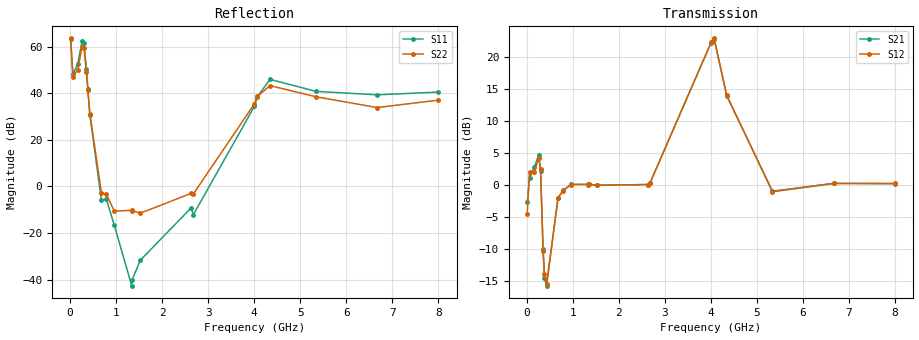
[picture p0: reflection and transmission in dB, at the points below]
!Agilent Technologies,N5230A,US43500312,A.07.50.67
!Agilent N5230A: A.07.50.67
!Date: Tuesday, June 09, 2015 15:38:11
!Correction: S11(Full 2 Port(1,2))
!S21(Full 2 Port(1,2))
!S12(Full 2 Port(1,2))
!S22(Full 2 Port(1,2))
!S2P File: Measurements: S11, S21, S12, S22:
# Hz S  MA  R 50
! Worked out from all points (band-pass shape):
!   1601 points, 10 MHz to 8 GHz, reference 50 ohm
!   highest |S21| = 22.90 dB at 4.07 GHz (marker M1); lowest = -15.7 dB at 429.5 MHz (marker M2)
!   |S21| within 3 dB of the highest: 3.919 GHz to 4.221 GHz (302.2 MHz wide, 7.43 % of centre)
!   lowest |S11| = -42.7 dB at 1.338 GHz (marker M3), VSWR 1.01, Z = 49.7 - j0.686 ohm
!   |S11| at or under -10 dB: 865.1 MHz to 2.134 GHz (1.269 GHz wide, 84.6 % of centre); 2.647 GHz to 2.845 GHz (197.8 MHz wide, 7.2 % of centre); 3.433 GHz to 3.482 GHz (48.8 MHz wide, 1.41 % of centre)
!   |S22| runs from -13.3 to 63.6 dB; largest |S21 - S12| = 0.38
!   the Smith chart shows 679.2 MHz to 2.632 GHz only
!   S11 on the Smith chart (normalised r, x): 679.2 MHz: 0.33, +0.14; 789 MHz: 0.35, -0.35; 958.8 MHz: 1.23, -0.24; 1.528 GHz: 0.95, +0.02; 2.632 GHz: 0.59, -0.40
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1e7  1494 171.1  0.7352 -1.6  0.5969 -32.9  1520 -19.4
5.99375e7  254.6 328.2  1.136 2.2  1.276 0.2  228.7 92.8
1.648062e8  426.6 407.6  1.376 10.1  1.261 9.7  321.2 128.4
2.596875e8  1316 407.2  1.732 8.4  1.636 3.4  1001 121.8
2.996375e8  1194 419.6  1.277 28.9  1.329 32.2  944.9 137.5
3.545688e8  327.8 460.0  0.3139 64.0  0.3047 64.3  287.3 187.5
3.845312e8  126.8 459.7  0.1863 51.8  0.2015 42.9  119.5 195.8
4.29475e8  34.12 460.3  0.1635 42.8  0.1677 41.7  36.76 213.5
6.791625e8  0.5164 522.1  0.7982 110.1  0.7933 110.4  0.7386 400.6
7.89025e8  0.5249 582.6  0.9071 85.3  0.9021 85.0  0.6739 487.4
9.588125e8  0.1483 679.7  1.012 79.3  1.009 79.3  0.2963 576.3
1.338338e9  0.007369 609.3  1.011 82.1  1.01 82.2  0.3068 756.6
1.343331e9  0.00971 581.3  1.011 82.1  1.012 82.2  0.303 759.1
1.5281e9  0.02613 520.3  0.9961 82.1  0.9981 82.1  0.2668 845.8
2.631719e9  0.3474 238.7  1.009 86.0  1.01 86.1  0.7112 1204.7
2.676662e9  0.2464 243.7  1.034 86.4  1.038 86.4  0.6886 1217.1
4.005e9  52.67 346.2  12.99 82.9  13.02 83.2  59.43 1528.6
4.069919e9  85.4 345.6  13.97 55.1  14.02 55.4  86.62 1518.7
4.344575e9  199.9 282.0  4.993 -44.4  5.022 -44.3  146.6 1450.8
5.338331e9  110.6 261.6  0.8957 13.5  0.887 13.6  84.64 1409.6
6.671662e9  92.99 291.5  1.032 11.8  1.029 12.3  49.6 1349.8
8e9  106.6 314.0  1.026 8.1  1.029 7.9  71.44 1313.9
